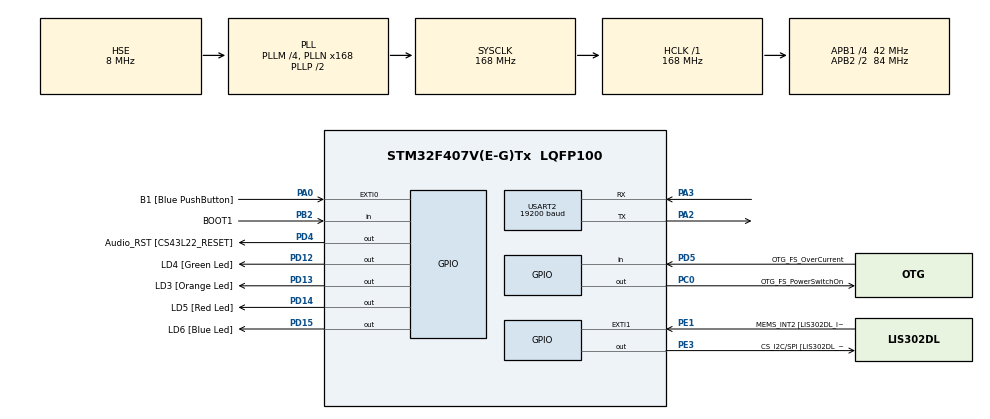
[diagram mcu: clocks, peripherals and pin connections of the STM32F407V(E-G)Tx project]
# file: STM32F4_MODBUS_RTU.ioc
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FREERTOS.Tasks01=defaultTask,0,128,StartDefaultTask,Default,NULL
Mcu.Family=STM32F4
Mcu.Name=STM32F407V(E-G)Tx
Mcu.Package=LQFP100
NVIC.PriorityGroup=NVIC_PRIORITYGROUP_4
NVIC.TIM6_DAC_IRQn=true\:0\:0\:false\:false\:true\:false\:true\:true
NVIC.TIM7_IRQn=true\:5\:0\:false\:false\:true\:true\:true\:true
NVIC.TimeBase=TIM6_DAC_IRQn
NVIC.TimeBaseIP=TIM6
NVIC.USART2_IRQn=true\:5\:0\:false\:false\:true\:true\:true\:true
PA0-WKUP.GPIO_Label=B1 [Blue PushButton]
PA0-WKUP.GPIO_ModeDefaultEXTI=GPIO_MODE_EVT_RISING
PA0-WKUP.GPIO_PuPd=GPIO_NOPULL
PA0-WKUP.Signal=GPXTI0
PA10.GPIO_Label=OTG_FS_ID
PA10.GPIO_Mode=GPIO_MODE_AF_PP
PA10.GPIO_PuPd=GPIO_NOPULL
PA10.GPIO_Speed=GPIO_SPEED_FREQ_LOW
PA10.Signal=USB_OTG_FS_ID
PA11.GPIO_Label=OTG_FS_DM
PA11.GPIO_Mode=GPIO_MODE_AF_PP
PA11.GPIO_PuPd=GPIO_NOPULL
PA11.GPIO_Speed=GPIO_SPEED_FREQ_LOW
PA11.Signal=USB_OTG_FS_DM
PA12.GPIO_Label=OTG_FS_DP
PA12.GPIO_Mode=GPIO_MODE_AF_PP
PA12.GPIO_PuPd=GPIO_NOPULL
PA12.GPIO_Speed=GPIO_SPEED_FREQ_LOW
PA12.Signal=USB_OTG_FS_DP
PA13.GPIO_Label=SWDIO
PA13.Signal=SYS_JTMS-SWDIO
PA14.GPIO_Label=SWCLK
PA14.Signal=SYS_JTCK-SWCLK
PA2.Mode=Asynchronous
PA2.Signal=USART2_TX
PA3.Mode=Asynchronous
PA3.Signal=USART2_RX
PA4.GPIO_Label=I2S3_WS [CS43L22_LRCK]
PA4.GPIO_Mode=GPIO_MODE_AF_PP
PA4.GPIO_PuPd=GPIO_NOPULL
PA4.GPIO_Speed=GPIO_SPEED_FREQ_LOW
PA4.Signal=I2S3_WS
PA5.GPIO_Label=SPI1_SCK [LIS302DL_SCL/SPC]
PA5.GPIO_Mode=GPIO_MODE_AF_PP
PA5.GPIO_PuPd=GPIO_NOPULL
PA5.GPIO_Speed=GPIO_SPEED_FREQ_LOW
PA5.Signal=SPI1_SCK
PA6.GPIO_Label=SPI1_MISO [LIS302DL_SDO]
PA6.GPIO_Mode=GPIO_MODE_AF_PP
PA6.GPIO_PuPd=GPIO_NOPULL
PA6.GPIO_Speed=GPIO_SPEED_FREQ_LOW
PA6.Signal=SPI1_MISO
PA7.GPIO_Label=SPI1_MOSI [LIS302DL_SDA/SDI/SDO]
PA7.GPIO_Mode=GPIO_MODE_AF_PP
PA7.GPIO_PuPd=GPIO_NOPULL
PA7.GPIO_Speed=GPIO_SPEED_FREQ_LOW
PA7.Signal=SPI1_MOSI
PA9.GPIO_Label=VBUS_FS
PA9.GPIO_Mode=GPIO_MODE_INPUT
PA9.GPIO_PuPd=GPIO_NOPULL
PA9.Signal=USB_OTG_FS_VBUS
PB10.GPIO_Label=CLK_IN [MP45DT02_CLK]
PB10.GPIO_Mode=GPIO_MODE_AF_PP
PB10.GPIO_PuPd=GPIO_NOPULL
PB10.GPIO_Speed=GPIO_SPEED_FREQ_LOW
PB10.Signal=I2S2_CK
PB2.GPIO_Label=BOOT1
PB2.GPIO_Mode=GPIO_MODE_INPUT
PB2.GPIO_PuPd=GPIO_NOPULL
PB2.Signal=GPIO_Input
PB3.GPIO_Label=SWO
PB3.Signal=SYS_JTDO-SWO
PB6.GPIO_Label=Audio_SCL [CS43L22_SCL]
PB6.GPIO_Mode=GPIO_MODE_AF_OD
PB6.GPIO_PuPd=GPIO_NOPULL
PB6.GPIO_Speed=GPIO_SPEED_FREQ_LOW
PB6.Signal=I2C1_SCL
PB9.GPIO_Label=Audio_SDA [CS43L22_SDA]
PB9.GPIO_Mode=GPIO_MODE_AF_OD
PB9.GPIO_PuPd=GPIO_NOPULL
PB9.GPIO_Speed=GPIO_SPEED_FREQ_LOW
PB9.Signal=I2C1_SDA
PC0.GPIO_Label=OTG_FS_PowerSwitchOn
PC0.GPIO_PuPd=GPIO_NOPULL
PC0.GPIO_Speed=GPIO_SPEED_FREQ_LOW
PC0.PinState=GPIO_PIN_SET
PC0.Signal=GPIO_Output
PC10.GPIO_Label=I2S3_SCK [CS43L22_SCLK]
PC10.GPIO_Mode=GPIO_MODE_AF_PP
PC10.GPIO_PuPd=GPIO_NOPULL
PC10.GPIO_Speed=GPIO_SPEED_FREQ_LOW
PC10.Signal=I2S3_CK
PC12.GPIO_Label=I2S3_SD [CS43L22_SDIN]
PC12.GPIO_Mode=GPIO_MODE_AF_PP
PC12.GPIO_PuPd=GPIO_NOPULL
PC12.GPIO_Speed=GPIO_SPEED_FREQ_LOW
PC12.Signal=I2S3_SD
PC14-OSC32_IN.GPIO_Label=PC14-OSC32_IN
PC14-OSC32_IN.Signal=RCC_OSC32_IN
PC15-OSC32_OUT.GPIO_Label=PC15-OSC32_OUT
PC15-OSC32_OUT.Signal=RCC_OSC32_OUT
PC3.GPIO_Label=PDM_OUT [MP45DT02_DOUT]
PC3.GPIO_Mode=GPIO_MODE_AF_PP
PC3.GPIO_PuPd=GPIO_NOPULL
PC3.GPIO_Speed=GPIO_SPEED_FREQ_LOW
PC3.Signal=I2S2_SD
PC7.GPIO_Label=I2S3_MCK [CS43L22_MCLK]
PC7.GPIO_Mode=GPIO_MODE_AF_PP
PC7.GPIO_PuPd=GPIO_NOPULL
PC7.GPIO_Speed=GPIO_SPEED_FREQ_LOW
PC7.Signal=I2S3_MCK
PD12.GPIO_Label=LD4 [Green Led]
PD12.GPIO_PuPd=GPIO_NOPULL
PD12.GPIO_Speed=GPIO_SPEED_FREQ_LOW
PD12.Signal=GPIO_Output
PD13.GPIO_Label=LD3 [Orange Led]
PD13.GPIO_PuPd=GPIO_NOPULL
PD13.GPIO_Speed=GPIO_SPEED_FREQ_LOW
PD13.Signal=GPIO_Output
PD14.GPIO_Label=LD5 [Red Led]
PD14.GPIO_PuPd=GPIO_NOPULL
PD14.GPIO_Speed=GPIO_SPEED_FREQ_LOW
PD14.Signal=GPIO_Output
PD15.GPIO_Label=LD6 [Blue Led]
PD15.GPIO_PuPd=GPIO_NOPULL
PD15.GPIO_Speed=GPIO_SPEED_FREQ_LOW
PD15.Signal=GPIO_Output
PD4.GPIO_Label=Audio_RST [CS43L22_RESET]
PD4.GPIO_PuPd=GPIO_NOPULL
PD4.GPIO_Speed=GPIO_SPEED_FREQ_LOW
PD4.Signal=GPIO_Output
PD5.GPIO_Label=OTG_FS_OverCurrent
PD5.GPIO_Mode=GPIO_MODE_INPUT
PD5.GPIO_PuPd=GPIO_NOPULL
PD5.Signal=GPIO_Input
PE1.GPIO_Label=MEMS_INT2 [LIS302DL_INT2]
PE1.GPIO_ModeDefaultEXTI=GPIO_MODE_EVT_RISING
PE1.GPIO_PuPd=GPIO_NOPULL
PE1.Signal=GPXTI1
PE3.GPIO_Label=CS_I2C/SPI [LIS302DL_CS_I2C/SPI]
PE3.GPIO_PuPd=GPIO_NOPULL
PE3.GPIO_Speed=GPIO_SPEED_FREQ_LOW
PE3.Signal=GPIO_Output
PH0-OSC_IN.GPIO_Label=PH0-OSC_IN
PH0-OSC_IN.Mode=HSE-External-Oscillator
PH0-OSC_IN.Signal=RCC_OSC_IN
PH1-OSC_OUT.GPIO_Label=PH1-OSC_OUT
PH1-OSC_OUT.Mode=HSE-External-Oscillator
PH1-OSC_OUT.Signal=RCC_OSC_OUT
ProjectManager.HeapSize=0x200
ProjectManager.StackSize=0x400
ProjectManager.TargetToolchain=MDK-ARM V5
RCC.48MHZClocksFreq_Value=48000000
RCC.AHBCLKDivider=RCC_SYSCLK_DIV1
RCC.AHBFreq_Value=168000000
RCC.APB1CLKDivider=RCC_HCLK_DIV4
RCC.APB1Freq_Value=42000000
RCC.APB1TimFreq_Value=84000000
RCC.APB2CLKDivider=RCC_HCLK_DIV2
RCC.APB2Freq_Value=84000000
RCC.APB2TimFreq_Value=168000000
RCC.ClockTypeHCLK=RCC_CLOCKTYPE_HCLK
RCC.ClockTypePCLK1=RCC_CLOCKTYPE_PCLK1
RCC.ClockTypePCLK2=RCC_CLOCKTYPE_PCLK2
RCC.ClockTypeSysClk=RCC_CLOCKTYPE_SYSCLK
RCC.CortexFreq_Value=168000000
RCC.EnableExtClockForI2S=false
RCC.EnableHSE=true
RCC.EnableHSERTCDevisor=false
RCC.EnableLSE=false
RCC.EnableLSERTC=false
RCC.ExtClockEnable=false
RCC.HCLKFreq_Value=168000000
RCC.HSEState=RCC_HSE_ON
RCC.HSE_VALUE=8000000
RCC.HSIState=RCC_HSI_OFF
RCC.HSI_VALUE=16000000
RCC.I2SEnable=false
RCC.IWDGEnable=false
RCC.LSE_VALUE=32768
RCC.LSIState=RCC_LSI_OFF
RCC.MCO1OutPutEnable=false
RCC.MCO2OutPutEnable=false
RCC.OscillatorTypeHSE=RCC_OSCILLATORTYPE_HSE
RCC.OscillatorTypeHSI=RCC_OSCILLATORTYPE_HSI
RCC.PLLM=4
RCC.PLLN=168
RCC.PLLP=RCC_PLLP_DIV2
RCC.PLLQ=7
RCC.PLLSourceVirtual=RCC_PLLSOURCE_HSE
RCC.PLLState=RCC_PLL_ON
RCC.RNGEnable=false
RCC.RTCEnable=false
RCC.SDIOEnable=false
RCC.SYSCLKFreq_VALUE=168000000
RCC.SYSCLKSource=RCC_SYSCLKSOURCE_PLLCLK
RCC.USBFSEnable=false
RCC.USBHSEnable=false
RCC.VCOOutputFreq_Value=336000000
TIM7.TIM_MasterOutputTrigger=TIM_TRGO_UPDATE
USART2.BaudRate=19200
USART2.VirtualMode=VM_ASYNC
VP_FREERTOS_VS_ENABLE.Mode=Enabled
VP_SYS_VS_tim6.Mode=TIM6
VP_TIM7_VS_ClockSourceINT.Mode=Enable_Timer
board=STM32F4DISCOVERY

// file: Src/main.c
/**
  ******************************************************************************
  * File Name          : main.c
  * Description        : Main program body
  ******************************************************************************
*/
#include "main.h"
#include "stm32f4xx_hal.h"
#include "cmsis_os.h"
TIM_HandleTypeDef htim7;
UART_HandleTypeDef huart2;
osThreadId defaultTaskHandle;
/* USER CODE BEGIN PV */
/* Private variables ---------------------------------------------------------*/
/* USER CODE END PV */
void SystemClock_Config(void);
void Error_Handler(void);
static void MX_GPIO_Init(void);
static void MX_USART2_UART_Init(void);
static void MX_TIM7_Init(void);
void StartDefaultTask(void const * argument);
/* USER CODE BEGIN PFP */
/* Private function prototypes -----------------------------------------------*/
extern void ModbusRTUTask(void const * argument);
extern void read_temps();
/* USER CODE END PFP */
int main(void)
{
  /* MCU Configuration----------------------------------------------------------*/
  /* Reset of all peripherals, Initializes the Flash interface and the Systick. */
  HAL_Init();
  /* Configure the system clock */
  SystemClock_Config();
  /* Initialize all configured peripherals */
  MX_GPIO_Init();
  MX_USART2_UART_Init();
  MX_TIM7_Init();
  /* Create the thread(s) */
  /* definition and creation of defaultTask */
  osThreadDef(defaultTask, StartDefaultTask, osPriorityNormal, 0, 128);
  defaultTaskHandle = osThreadCreate(osThread(defaultTask), NULL);
  /* Start scheduler */
  osKernelStart();
  /* We should never get here as control is now taken by the scheduler */
  /* Infinite loop */
  while (1)
  {
  }
}
/** System Clock Configuration
*/
void SystemClock_Config(void)
{

  RCC_OscInitTypeDef RCC_OscInitStruct;
  RCC_ClkInitTypeDef RCC_ClkInitStruct;
    /**Configure the main internal regulator output voltage
    */
  __HAL_RCC_PWR_CLK_ENABLE();

  __HAL_PWR_VOLTAGESCALING_CONFIG(PWR_REGULATOR_VOLTAGE_SCALE1);

    /**Initializes the CPU, AHB and APB busses clocks
    */
  RCC_OscInitStruct.OscillatorType = RCC_OSCILLATORTYPE_HSE;
  RCC_OscInitStruct.HSEState = RCC_HSE_ON;
  RCC_OscInitStruct.PLL.PLLState = RCC_PLL_ON;
  RCC_OscInitStruct.PLL.PLLSource = RCC_PLLSOURCE_HSE;
  RCC_OscInitStruct.PLL.PLLM = 4;
  RCC_OscInitStruct.PLL.PLLN = 168;
  RCC_OscInitStruct.PLL.PLLP = RCC_PLLP_DIV2;
  RCC_OscInitStruct.PLL.PLLQ = 7;
  if (HAL_RCC_OscConfig(&RCC_OscInitStruct) != HAL_OK)
  {
    Error_Handler();
  }
    /**Initializes the CPU, AHB and APB busses clocks
    */
  RCC_ClkInitStruct.ClockType = RCC_CLOCKTYPE_HCLK|RCC_CLOCKTYPE_SYSCLK
                              |RCC_CLOCKTYPE_PCLK1|RCC_CLOCKTYPE_PCLK2;
  RCC_ClkInitStruct.SYSCLKSource = RCC_SYSCLKSOURCE_PLLCLK;
  RCC_ClkInitStruct.AHBCLKDivider = RCC_SYSCLK_DIV1;
  RCC_ClkInitStruct.APB1CLKDivider = RCC_HCLK_DIV4;
  RCC_ClkInitStruct.APB2CLKDivider = RCC_HCLK_DIV2;
  if (HAL_RCC_ClockConfig(&RCC_ClkInitStruct, FLASH_LATENCY_5) != HAL_OK)
  {
    Error_Handler();
  }
    /**Configure the Systick interrupt time
    */
  HAL_SYSTICK_Config(HAL_RCC_GetHCLKFreq()/1000);
    /**Configure the Systick
    */
  HAL_SYSTICK_CLKSourceConfig(SYSTICK_CLKSOURCE_HCLK);
  /* SysTick_IRQn interrupt configuration */
  HAL_NVIC_SetPriority(SysTick_IRQn, 15, 0);
}
/* TIM7 init function */
static void MX_TIM7_Init(void)
{
  TIM_MasterConfigTypeDef sMasterConfig;
  htim7.Instance = TIM7;
  htim7.Init.Prescaler = 0;
  htim7.Init.CounterMode = TIM_COUNTERMODE_UP;
  htim7.Init.Period = 0;
  if (HAL_TIM_Base_Init(&htim7) != HAL_OK)
  {
    Error_Handler();
  }
  sMasterConfig.MasterOutputTrigger = TIM_TRGO_UPDATE;
  sMasterConfig.MasterSlaveMode = TIM_MASTERSLAVEMODE_DISABLE;
  if (HAL_TIMEx_MasterConfigSynchronization(&htim7, &sMasterConfig) != HAL_OK)
  {
    Error_Handler();
  }
}
/* USART2 init function */
static void MX_USART2_UART_Init(void)
{
  huart2.Instance = USART2;
  huart2.Init.BaudRate = 9600;
  huart2.Init.WordLength = UART_WORDLENGTH_8B;
  huart2.Init.StopBits = UART_STOPBITS_1;
  huart2.Init.Parity = UART_PARITY_NONE;
  huart2.Init.Mode = UART_MODE_TX_RX;
  huart2.Init.HwFlowCtl = UART_HWCONTROL_NONE;
  huart2.Init.OverSampling = UART_OVERSAMPLING_16;
  if (HAL_UART_Init(&huart2) != HAL_OK)
  {
    Error_Handler();
  }
}
static void MX_GPIO_Init(void)
{
  GPIO_InitTypeDef GPIO_InitStruct;
  /* GPIO Ports Clock Enable */
  __HAL_RCC_GPIOE_CLK_ENABLE();
  __HAL_RCC_GPIOC_CLK_ENABLE();
  __HAL_RCC_GPIOH_CLK_ENABLE();
  __HAL_RCC_GPIOA_CLK_ENABLE();
  __HAL_RCC_GPIOB_CLK_ENABLE();
  __HAL_RCC_GPIOD_CLK_ENABLE();
  /*Configure GPIO pin Output Level */
  HAL_GPIO_WritePin(CS_I2C_SPI_GPIO_Port, CS_I2C_SPI_Pin, GPIO_PIN_RESET);
  /*Configure GPIO pin Output Level */
  HAL_GPIO_WritePin(OTG_FS_PowerSwitchOn_GPIO_Port, OTG_FS_PowerSwitchOn_Pin, GPIO_PIN_SET);
  /*Configure GPIO pin Output Level */
  HAL_GPIO_WritePin(GPIOD, LD4_Pin|LD3_Pin|LD5_Pin|LD6_Pin
                          |Audio_RST_Pin, GPIO_PIN_RESET);
	GPIO_InitStruct.Pin = GPIO_PIN_5|GPIO_PIN_4;
  GPIO_InitStruct.Mode = GPIO_MODE_OUTPUT_PP;
  GPIO_InitStruct.Pull = GPIO_NOPULL;
  GPIO_InitStruct.Speed = GPIO_SPEED_FREQ_LOW;
  HAL_GPIO_Init(GPIOC, &GPIO_InitStruct);
  /*Configure GPIO pins : LD4_Pin LD3_Pin LD5_Pin LD6_Pin
                           Audio_RST_Pin */
  GPIO_InitStruct.Pin = LD4_Pin|LD3_Pin|LD5_Pin|LD6_Pin
                          |Audio_RST_Pin;
  GPIO_InitStruct.Mode = GPIO_MODE_OUTPUT_PP;
  GPIO_InitStruct.Pull = GPIO_NOPULL;
  GPIO_InitStruct.Speed = GPIO_SPEED_FREQ_LOW;
  HAL_GPIO_Init(GPIOD, &GPIO_InitStruct);
	GPIO_InitStruct.Pin = GPIO_PIN_5|GPIO_PIN_7;
	GPIO_InitStruct.Mode = GPIO_MODE_OUTPUT_PP;
  GPIO_InitStruct.Pull = GPIO_PULLUP;
  GPIO_InitStruct.Speed = GPIO_SPEED_FREQ_VERY_HIGH;
  HAL_GPIO_Init(GPIOA, &GPIO_InitStruct);
	GPIO_InitStruct.Pin = GPIO_PIN_6;
  GPIO_InitStruct.Mode = GPIO_MODE_INPUT; // digital Input
  GPIO_InitStruct.Pull = GPIO_NOPULL;
  HAL_GPIO_Init(GPIOA, &GPIO_InitStruct);
  /*Configure GPIO pins : PE7 PE9 */
  GPIO_InitStruct.Pin = GPIO_PIN_7|GPIO_PIN_9;
  GPIO_InitStruct.Mode = GPIO_MODE_OUTPUT_PP;
  GPIO_InitStruct.Pull = GPIO_NOPULL;
  GPIO_InitStruct.Speed = GPIO_SPEED_FREQ_LOW;
  HAL_GPIO_Init(GPIOE, &GPIO_InitStruct);
}
/* StartDefaultTask function */
void StartDefaultTask(void const * argument)
{
	osThreadDef(read_temps, read_temps, osPriorityNormal, 0, configMINIMAL_STACK_SIZE);
  osThreadCreate(osThread(read_temps), NULL);
  /* USER CODE BEGIN 5 */
	osThreadDef(ModbusRTUTask, ModbusRTUTask, osPriorityNormal, 0, configMINIMAL_STACK_SIZE);
  osThreadCreate(osThread(ModbusRTUTask), NULL);
  /* Infinite loop */
  for(;;)
  {
    osDelay(1);
  }
  /* USER CODE END 5 */
}
void HAL_TIM_PeriodElapsedCallback(TIM_HandleTypeDef *htim)
{
  if (htim->Instance == TIM6) {
    HAL_IncTick();
  }
}
void Error_Handler(void)
{
  while(1)
  {
  }
}

/************************ (C) COPYRIGHT STMicroelectronics *****END OF FILE****/
